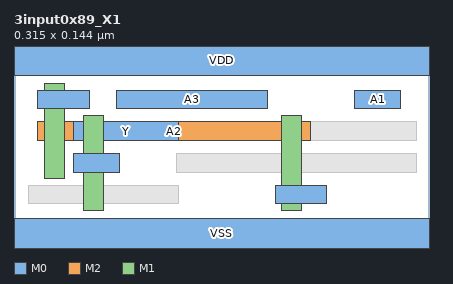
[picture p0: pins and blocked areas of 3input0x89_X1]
MACRO 3input0x89_X1
  CLASS CORE ;
  ORIGIN 0 0 ;
  FOREIGN 3input0x89_X1 0 0 ;
  SIZE 0.3150 BY 0.1440 ;
  SYMMETRY X Y ;
  SITE coresite ;
  PIN A1
    DIRECTION INPUT ;
    USE SIGNAL ;
    PORT
      LAYER M0 ;
        RECT 0.2580 0.1010 0.2930 0.1150 ;
    END
  END A1
  PIN A2
    DIRECTION INPUT ;
    USE SIGNAL ;
    PORT
      LAYER M2 ;
        RECT 0.0180 0.0770 0.2250 0.0910 ;
      LAYER M1 ;
        RECT 0.0230 0.0480 0.0380 0.1200 ;
        RECT 0.2030 0.0240 0.2180 0.0960 ;
      LAYER M0 ;
        RECT 0.1980 0.0290 0.2370 0.0430 ;
        RECT 0.0180 0.1010 0.0570 0.1150 ;
    END
  END A2
  PIN A3
    DIRECTION INPUT ;
    USE SIGNAL ;
    PORT
      LAYER M0 ;
        RECT 0.0780 0.1010 0.1920 0.1150 ;
    END
  END A3
  PIN Y
    DIRECTION OUTPUT ;
    USE SIGNAL ;
    PORT
      LAYER M1 ;
        RECT 0.0530 0.0240 0.0680 0.0960 ;
      LAYER M0 ;
        RECT 0.0450 0.0770 0.1250 0.0910 ;
        RECT 0.0450 0.0530 0.0800 0.0670 ;
    END
  END Y
  PIN VDD
    DIRECTION INOUT ;
    USE POWER ;
    SHAPE ABUTMENT ;
    PORT
      LAYER M0 ;
        RECT 0.0000 0.1260 0.3150 0.1620 ;
    END
  END VDD
  PIN VSS
    DIRECTION INOUT ;
    USE GROUND ;
    SHAPE ABUTMENT ;
    PORT
      LAYER M0 ;
        RECT 0.0000 -0.0180 0.3150 0.0180 ;
    END
  END VSS
  OBS
    LAYER V1 ;
      RECT 0.0230 0.0770 0.0370 0.0910 ;
      RECT 0.2030 0.0770 0.2170 0.0910 ;
    LAYER V0 ;
      RECT 0.0530 0.0770 0.0670 0.0910 ;
      RECT 0.0530 0.0530 0.0670 0.0670 ;
      RECT 0.0230 0.1010 0.0370 0.1150 ;
      RECT 0.2030 0.0290 0.2170 0.0430 ;
    LAYER M0 ;
      RECT 0.0110 0.0290 0.1250 0.0430 ;
      RECT 0.1230 0.0530 0.3050 0.0670 ;
      RECT 0.1910 0.0770 0.3050 0.0910 ;
  END
END 3input0x89_X1
